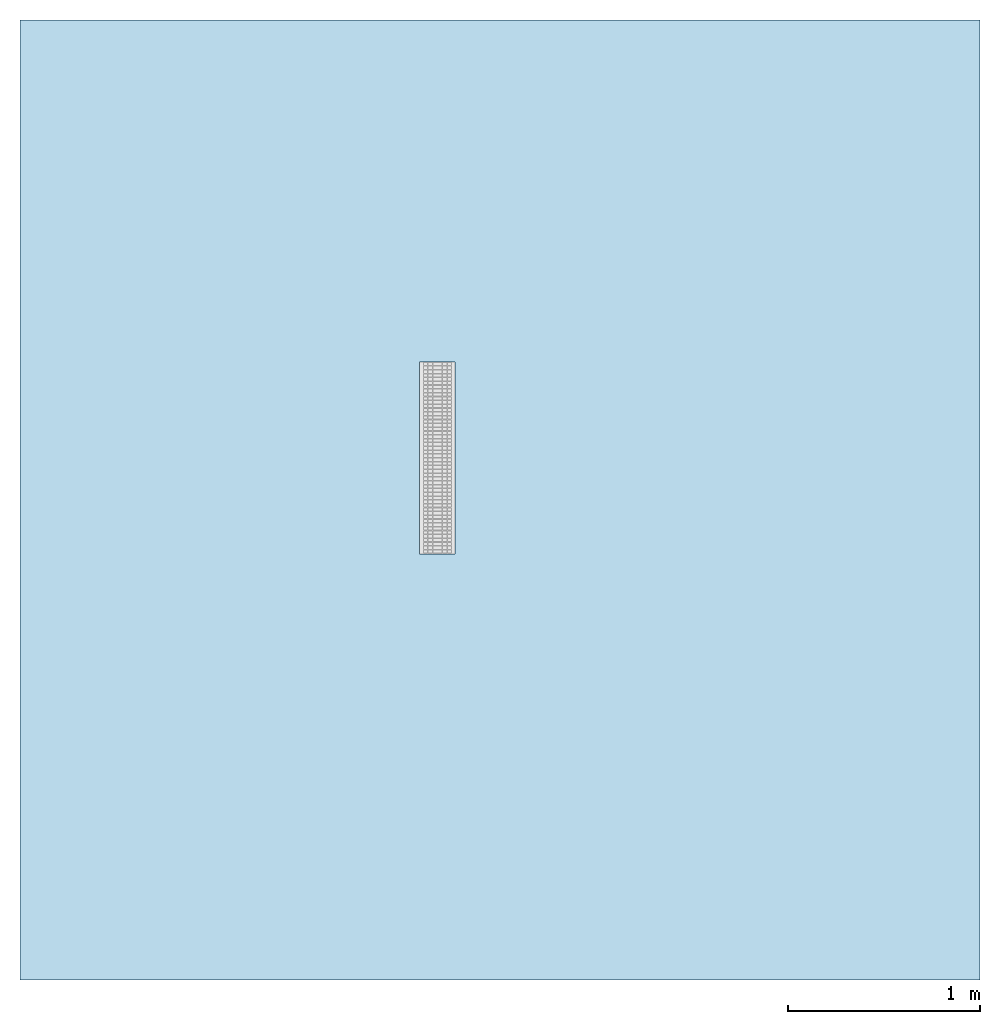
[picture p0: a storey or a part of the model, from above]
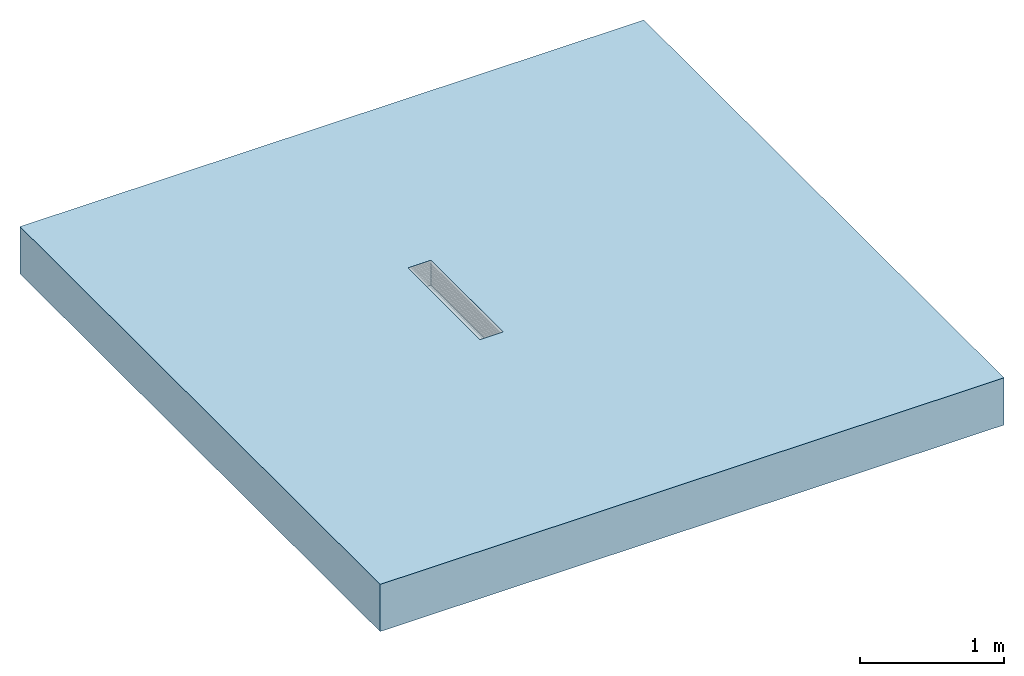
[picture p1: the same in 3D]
Properties of the parts of a building model (IFC2X3)

# File
Description: ViewDefinition [CoordinationView]
File name: 24150 - No 0.0 Constant Depth Channel - 1000mm LG - Invert Depth 185mm.ifc
Time: 2013-10-17T16:55:56
Written by: Autodesk Revit 2013
Made in: 20120221_2030(x64)

# IfcProject, Project Number
LongName: Project Name; Phase: Project Status

# IfcSite, Default
RefLatitude: 42, 21, 30, 344238; RefLongitude: -71, -3, -35, -194702; RefElevation: 0 mm

# IfcBuilding
Pset_BuildingCommon - NumberOfStoreys: 1
Other - Project Issue Date: Issue Date; Project Name: Project Name; Project Status: Project Status; Project Number: Project Number; Project Address: ## Street City, State Zip; Client Name: Owner

# IfcBuildingStorey, Level 1
LongName: Level 1; Elevation: 0 mm
Constraints - Elevation Base: 0; Elevation: 0 mm
Graphics - Symbol: M_Level Head - Circle: M_Level Head - Circle; Symbol at End 2 Default: yes; Color: 0; Line Pattern: Center; Symbol at End 1 Default: no; Line Weight: 1
Identity Data - Structural: no; Name: Level 1; Building Story: yes
Dimensions - Computation Height: 0 mm

# IfcBuildingElementProxy: 24150 - No 0.0 Constant Depth Channel - 1000mm LG - Invert Depth 185mm, Civil-Drainage-Channel-ACO-MultiDrain-M150DS-Channel-System-Custom_Final FL:24150 - No 0.0 Constant Depth Channel - 1000mm LG - Invert Depth 185mm:24150 - No 0.0 Constant Depth Channel - 1000mm LG - Invert Depth 185mm:199235
In: Level 1
Material: Vienite® Synthetic Resin Concrete
Construction - 23159 - Universal Endcap (Male End): no; 13049 - Grating - Mesh - Stainless Steel - 500mm Long: no; 23159 - Universal Endcap (Female End): no; 13048 - Grating - Mesh - Stainless Steel - 1000mm Long: no; Grating_1000mm: yes; 24157_Shallow Depth Channel with seal: no; 24156_Shallow Depth Channel: no; 24158_Sump Unit: no; Constant Depth Channel_1000: yes; Constant Depth Channel_500: no; Grating_500mm: no
Phasing - Phase Created: New Construction
Constraints - Moves With Nearby Elements: no; Level: Level: Level 1
Dimensions - Custom cut void length: 0 mm; Volume: 14075930 mm3; Length: 1000 mm; FloorCut_Length: -1000 mm; EndCap Position: 1000 mm; FloorCut_HorPosition: 92.5 mm; EndCap_Height: 210 mm; FloorCut_Depth: 210 mm; Depth: 210 mm; Mesh grating length: -1000 mm; FloorCut_Width: 185 mm; InvDepth: 110 mm
Pset_BuildingElementProxyCommon - Reference: 24150 - No 0.0 Constant Depth Channel - 1000mm LG - Invert Depth 185mm
Identity Data - Fax: +44 (0)1462 815895; Assembly Description: Rain Water Drainage; Maintenance guidelines: http://www.aco.co.uk/download.php?id=173; OmniClass Number: 23.70.50.24; Watermark 2: This file is water marked and users are prohibited to reproduce, adapt, distribute this information; Model Description: Channel drainage system; Telephone: +44 (0)1462 816666; Watermarked By: www.aco.co.uk; Product Code: 24150; Price: POA - contact ACO; e-mail Sales: customersupport@aco.co.uk; Installation guidelines: http://www.aco.co.uk/download.php?id=173; OmniClass Title: Rainwater Removal; URL: www.aco.co.uk; Manufacturer: ACO Technologies PLC - ACO Water Management Division; e-mail Technical: technical@aco.co.uk; Type Comments: ACO MultiDrain M150DS 0.0 Constant Depth Channel 1000mm Long; Watermarked With: BIM Manager Premium Suite; Product Page URL: http://www.aco.co.uk/product_detail.php?id=15; Assembly Code: D2040; Address: ACO Business Park, Hitchin Road, Shefford, Bedfordshire, United Kingdom SG17 5TE; Watermark 1: This file is the property of ACO Technologies PLC; Model: ACO MultiDrain MD - M150DS; Product brochure: http://www.aco.co.uk/download.php?id=173; Cost: 0
Model Properties - End Cap Product code 23159: No 306 Universal End Cap - 185mm wide x 310mm long - Spigot Ø160mm x 75mm long - Silver - Polypropylene - 0.3kg; Grating Product code 13048: Load Class C250 - Mesh Stainless Steel Grade 304 13048DL 1000mm long - 23x17mm hole - Intake Area 115100mm²/m- 7.4kg; Grating Product code 13049: Load Class C250 - Mesh Stainless Steel Grade 304 13049DL 500mm long - 23x17mm hole - Intake Area 115100mm²/m- 3.7kg
General - TagNumber: 0; SerialNumber: 0
Green Building Properties - Channel Recyclable: Fully recyclable; Edge Rail Recyclable: Fully recyclable; Edge Rail Recycled Material Content: Between 40% - 90%; Channel Recycled Material Content: 20% minimum
Data - Hydraulic Performance: http://www.aco.co.uk/download.php?id=173; Concrete Surround Volume - Load Class B 125 - C 250 - Concrete Pavement: 0.14m³/m; Product Weight: 23.3 Kg; Invert Depth: 185mm; Concrete Surround Volume - Load Class A 15 - Concrete Pavement: 0.09m³/m; Product Dimensions: 1000mm x 185mm x 210mm (LxWxH); Load Class: A 15 - D 400; Installation - Concrete Grade: Refer to brochure; Concrete Surround Volume - Load Class D 400 - Concrete Pavement: 0.21m³/m; ACO Hydraulic Design Software: http://www.acodesign.co.uk; Product Standard: BS EN 1433:2002, CE marked; Pre-formed Outlet Ø: N/A; Channel C.S.A: 0.020m²
Other - Revision: 1; CreatedBy: www.aco.co.uk
Materials and Finishes - Edge Rail Material: Stainless Steel Grade 304; Channel Material: Vienite® Synthetic Resin Concrete; Channel Colour: Brown; Edge Rail Colour: Self

# IfcOpeningElement: Recess
In: Level 1
Phasing - Phase Created: New Construction
Structural - Enable Analytical Model: no; Structural: no
Dimensions - Perimeter: 20000 mm; Area: 25000000 mm2; Volume: 9961150000 mm3; Thickness: 400 mm
Constraints - Room Bounding: yes; Level: Level: Level 1; Height Offset From Level: 0 mm; Related to Mass: no
Analytical Properties - Absorptance: 0.1; Roughness: 1
Graphics - Coarse Scale Fill Color: 0
Construction - Default Thickness: 400 mm; Function: 0

# IfcSlab: Floor:Generic Floor - 400mm, Floor:Generic Floor - 400mm:193825
In: Level 1
PredefinedType: FLOOR; Material: Default Roof 400 mm
Phasing - Phase Created: New Construction
Structural - Enable Analytical Model: no; Structural: no
Dimensions - Perimeter: 20000 mm; Area: 25000000 mm2; Volume: 9961150000 mm3; Thickness: 400 mm
Constraints - Room Bounding: yes; Level: Level: Level 1; Height Offset From Level: 0 mm; Related to Mass: no
Pset_SlabCommon - Reference: Generic Floor - 400mm; IsExternal: no; LoadBearing: yes
Analytical Properties - Absorptance: 0.1; Roughness: 1
Graphics - Coarse Scale Fill Color: 0
Construction - Default Thickness: 400 mm; Function: 0
